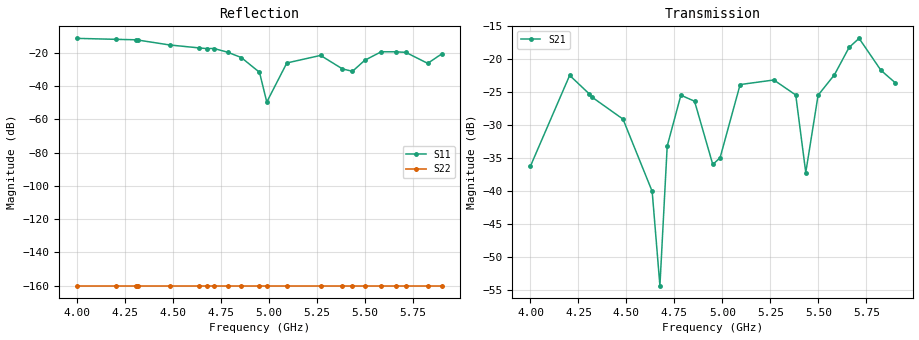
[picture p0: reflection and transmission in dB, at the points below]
! NanoVNA-App
! Date: 2024-02-22 10:33:23
! Start: 4GHz Stop: 5.9GHz Points: 801
! S-Parameter data: F S11 S21 S12 S22
# Hz S RI R 50
!  Frequency  S11_Real  S11_Imag  S21_Real  S21_Imag  S12_Real  S12_Imag  S22_Real  S22_Imag
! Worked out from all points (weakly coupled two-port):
!   801 points, 4 GHz to 5.9 GHz, reference 50 ohm
!   highest |S21| = -16.86 dB at 5.712 GHz (marker M1); lowest = -54.3 dB at 4.675 GHz (marker M2)
!   lowest |S11| = -49.7 dB at 4.988 GHz (marker M3), VSWR 1.01, Z = 50.3 + j0.143 ohm
!   |S11| at or under -10 dB: start of sweep to end of sweep
!   S12 and S22 are empty: the file has one direction only
!   S11 on the Smith chart (normalised r, x): 4 GHz: 1.21, +0.57; 4.306 GHz: 1.45, -0.40; 5.66 GHz: 0.81, -0.05; 5.9 GHz: 1.04, -0.18
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4e9  0.1517 0.2208  0.00245 0.0153  0 0  0 0
4.20425e9  0.2504 -0.000467  -0.0672 0.0341  0 0  0 0
4.306375e9  0.2042 -0.1313  -0.0454 -0.0302  0 0  0 0
4.31825e9  0.1886 -0.1445  -0.0394 -0.0337  0 0  0 0
4.482125e9  0.0302 -0.1669  -0.00958 -0.0338  0 0  0 0
4.634125e9  -0.0389 -0.1331  0.00948 -0.00309  0 0  0 0
4.6745e9  -0.0502 -0.1224  0.000782 0.00176  0 0  0 0
4.7125e9  -0.0755 -0.1093  -0.0165 0.0145  0 0  0 0
4.78375e9  -0.0901 -0.05  -0.0533 0.000221  0 0  0 0
4.855e9  -0.0709 -0.00647  -0.0363 -0.0314  0 0  0 0
4.95e9  -0.0128 0.0222  0.000964 -0.0159  0 0  0 0
4.988e9  0.00296 0.00142  0.00565 -0.017  0 0  0 0
5.0925e9  0.0111 -0.0476  0.0412 -0.0492  0 0  0 0
5.26825e9  -0.0811 -0.0151  0.0695 0.000667  0 0  0 0
5.38225e9  -0.00459 0.0321  0.0495 0.0203  0 0  0 0
5.4345e9  0.0266 0.00663  0.00308 0.0135  0 0  0 0
5.498625e9  0.0293 -0.0511  -0.0511 -0.0149  0 0  0 0
5.584125e9  -0.0518 -0.0925  -0.0322 -0.0691  0 0  0 0
5.660125e9  -0.1019 -0.028  0.0287 -0.1191  0 0  0 0
5.712375e9  -0.0973 0.0299  0.0531 -0.1334  0 0  0 0
5.826375e9  0.0427 0.021  0.0669 -0.0478  0 0  0 0
5.9e9  0.0283 -0.0874  0.0628 0.0214  0 0  0 0
